VERSION 5.8 ;
BUSBITCHARS "[]" ;
DIVIDERCHAR "/" ;
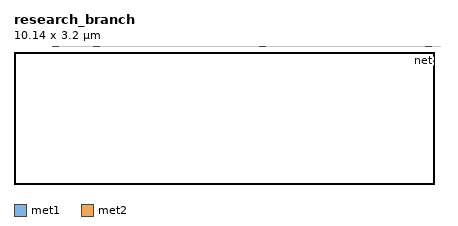
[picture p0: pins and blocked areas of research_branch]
MACRO research_branch
  CLASS BLOCK ;
  ORIGIN 0.930 4.870 ;
  SIZE 10.140 BY 3.200 ;
  SYMMETRY X Y ;
  PIN net
    DIRECTION INOUT ;
    USE SIGNAL ;
    PORT
      LAYER met1 ;
        RECT 0.000 0.060 0.140 0.200 ;
      LAYER met2 ;
        RECT 1.000 2.060 1.140 2.200 ;
      LAYER met2 ;
        RECT 5.000 2.560 5.140 2.700 ;
      LAYER met2 ;
        RECT 9.000 3.060 9.140 3.200 ;
    END
  END net
  OBS
      LAYER met1 ;
        RECT 0.940 0.000 1.200 0.060 ;
        RECT 4.940 0.000 5.200 0.060 ;
        RECT 8.940 0.000 9.200 0.060 ;
        RECT 0.140 0.060 10.140 0.200 ;
        RECT 0.940 0.200 1.200 0.260 ;
        RECT 4.940 0.200 5.200 0.260 ;
        RECT 8.940 0.200 9.200 0.260 ;
      LAYER met2 ;
        RECT 0.940 0.000 1.200 0.260 ;
        RECT 4.940 0.000 5.200 0.260 ;
        RECT 8.940 0.000 9.200 0.260 ;
        RECT 1.000 0.260 1.140 2.060 ;
        RECT 5.000 0.260 5.140 2.560 ;
        RECT 9.000 0.260 9.140 3.060 ;
  END
END research_branch
END LIBRARY
